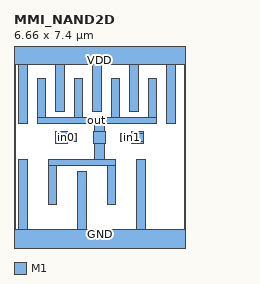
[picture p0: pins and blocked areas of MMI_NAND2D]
MACRO MMI_NAND2D
	CLASS CORE ;
	FOREIGN MMI_NAND2D 0 0 ;
	SIZE 6.66 BY 7.4 ;
	SYMMETRY X Y ;
	SITE CORE1 ;
	PIN out
		DIRECTION output ;
		USE SIGNAL ;
		PORT
			LAYER M1 ;
			RECT 0.9 4.83 1.24 6.36 ;
			LAYER M1 ;
			RECT 2.34 4.83 2.68 6.36 ;
			LAYER M1 ;
			RECT 3.78 4.83 4.12 6.36 ;
			LAYER M1 ;
			RECT 5.22 4.83 5.56 6.36 ;
			LAYER M1 ;
			RECT 0.9 4.6 5.56 4.83 ;
			LAYER M1 ;
			RECT 3.135 4.295 3.525 4.6 ;
			LAYER M1 ;
			RECT 3.105 3.845 3.555 4.295 ;
			LAYER M1 ;
			RECT 3.135 3.22 3.525 3.845 ;
			LAYER M1 ;
			RECT 1.33 2.99 3.97 3.22 ;
			LAYER M1 ;
			RECT 1.33 1.46 1.67 2.99 ;
			LAYER M1 ;
			RECT 3.63 1.46 3.97 2.99 ;
		END
		AntennaDiffArea 5.9616 ;
	END out
	PIN in1
		DIRECTION input ;
		USE SIGNAL ;
		PORT
			LAYER M1 ;
			RECT 4.585 4.24 5.035 4.295 ;
			LAYER M1 ;
			RECT 4.145 3.9 5.035 4.24 ;
			LAYER M1 ;
			RECT 4.585 3.845 5.035 3.9 ;
		END
		AntennaGateArea 2.6496 ;
	END in1
	PIN GND
		DIRECTION inout ;
		USE GROUND ;
		PORT
			LAYER M1 ;
			RECT 0.18 0.5 0.52 3.22 ;
			LAYER M1 ;
			RECT 2.48 0.5 2.82 2.74 ;
			LAYER M1 ;
			RECT 4.78 0.5 5.12 3.22 ;
			LAYER M1 ;
			RECT 0 -0.5 6.66 0.5 ;
		END
	END GND
	PIN VDD
		DIRECTION inout ;
		USE POWER ;
		PORT
			LAYER M1 ;
			RECT 0 6.9 6.66 7.9 ;
			LAYER M1 ;
			RECT 0.18 4.6 0.52 6.9 ;
			LAYER M1 ;
			RECT 1.62 5.08 1.96 6.9 ;
			LAYER M1 ;
			RECT 3.06 5.08 3.4 6.9 ;
			LAYER M1 ;
			RECT 4.5 5.08 4.84 6.9 ;
			LAYER M1 ;
			RECT 5.94 4.6 6.28 6.9 ;
		END
	END VDD
	PIN in0
		DIRECTION input ;
		USE SIGNAL ;
		PORT
			LAYER M1 ;
			RECT 1.625 4.24 2.075 4.295 ;
			LAYER M1 ;
			RECT 1.625 3.9 2.445 4.24 ;
			LAYER M1 ;
			RECT 1.625 3.845 2.075 3.9 ;
		END
		AntennaGateArea 2.6496 ;
	END in0
	OBS
	END
END MMI_NAND2D
